VERSION 5.7 ;
BUSBITCHARS "[]" ;
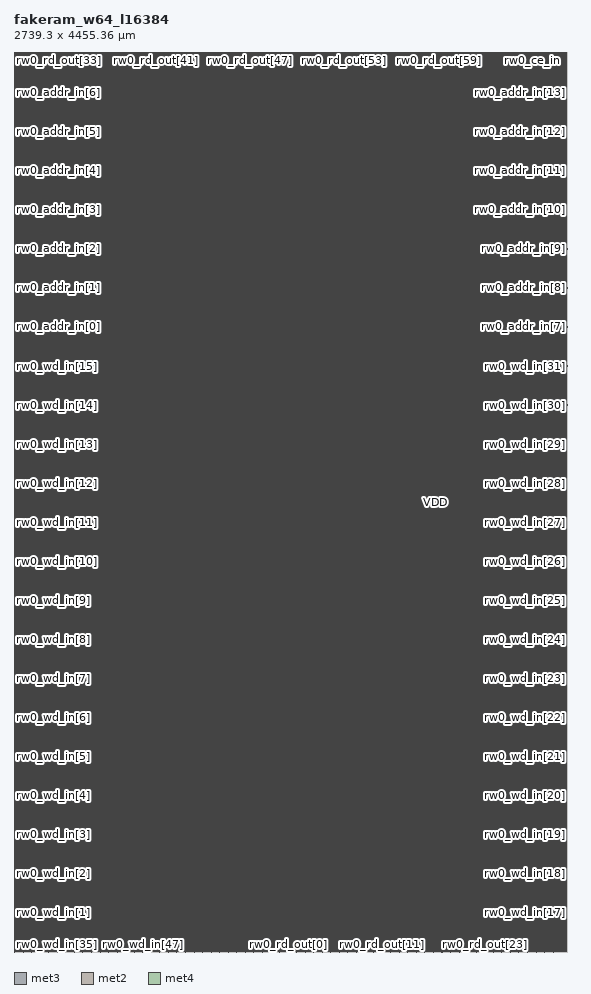
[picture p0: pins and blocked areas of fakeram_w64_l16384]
MACRO fakeram_w64_l16384
  FOREIGN fakeram_w64_l16384 0 0 ;
  SYMMETRY X Y R90 ;
  SIZE 2739.300 BY 4455.360 ;
  CLASS BLOCK ;
  PIN rw0_wd_in[0]
    DIRECTION INPUT ;
    USE SIGNAL ;
    SHAPE ABUTMENT ;
    PORT
      LAYER met3 ;
      RECT 0.000 3.930 0.900 4.230 ;
    END
  END rw0_wd_in[0]
  PIN rw0_wd_in[1]
    DIRECTION INPUT ;
    USE SIGNAL ;
    SHAPE ABUTMENT ;
    PORT
      LAYER met3 ;
      RECT 0.000 197.050 0.900 197.350 ;
    END
  END rw0_wd_in[1]
  PIN rw0_wd_in[2]
    DIRECTION INPUT ;
    USE SIGNAL ;
    SHAPE ABUTMENT ;
    PORT
      LAYER met3 ;
      RECT 0.000 390.170 0.900 390.470 ;
    END
  END rw0_wd_in[2]
  PIN rw0_wd_in[3]
    DIRECTION INPUT ;
    USE SIGNAL ;
    SHAPE ABUTMENT ;
    PORT
      LAYER met3 ;
      RECT 0.000 583.290 0.900 583.590 ;
    END
  END rw0_wd_in[3]
  PIN rw0_wd_in[4]
    DIRECTION INPUT ;
    USE SIGNAL ;
    SHAPE ABUTMENT ;
    PORT
      LAYER met3 ;
      RECT 0.000 776.410 0.900 776.710 ;
    END
  END rw0_wd_in[4]
  PIN rw0_wd_in[5]
    DIRECTION INPUT ;
    USE SIGNAL ;
    SHAPE ABUTMENT ;
    PORT
      LAYER met3 ;
      RECT 0.000 969.530 0.900 969.830 ;
    END
  END rw0_wd_in[5]
  PIN rw0_wd_in[6]
    DIRECTION INPUT ;
    USE SIGNAL ;
    SHAPE ABUTMENT ;
    PORT
      LAYER met3 ;
      RECT 0.000 1162.650 0.900 1162.950 ;
    END
  END rw0_wd_in[6]
  PIN rw0_wd_in[7]
    DIRECTION INPUT ;
    USE SIGNAL ;
    SHAPE ABUTMENT ;
    PORT
      LAYER met3 ;
      RECT 0.000 1355.770 0.900 1356.070 ;
    END
  END rw0_wd_in[7]
  PIN rw0_wd_in[8]
    DIRECTION INPUT ;
    USE SIGNAL ;
    SHAPE ABUTMENT ;
    PORT
      LAYER met3 ;
      RECT 0.000 1548.890 0.900 1549.190 ;
    END
  END rw0_wd_in[8]
  PIN rw0_wd_in[9]
    DIRECTION INPUT ;
    USE SIGNAL ;
    SHAPE ABUTMENT ;
    PORT
      LAYER met3 ;
      RECT 0.000 1742.010 0.900 1742.310 ;
    END
  END rw0_wd_in[9]
  PIN rw0_wd_in[10]
    DIRECTION INPUT ;
    USE SIGNAL ;
    SHAPE ABUTMENT ;
    PORT
      LAYER met3 ;
      RECT 0.000 1935.130 0.900 1935.430 ;
    END
  END rw0_wd_in[10]
  PIN rw0_wd_in[11]
    DIRECTION INPUT ;
    USE SIGNAL ;
    SHAPE ABUTMENT ;
    PORT
      LAYER met3 ;
      RECT 0.000 2128.250 0.900 2128.550 ;
    END
  END rw0_wd_in[11]
  PIN rw0_wd_in[12]
    DIRECTION INPUT ;
    USE SIGNAL ;
    SHAPE ABUTMENT ;
    PORT
      LAYER met3 ;
      RECT 0.000 2321.370 0.900 2321.670 ;
    END
  END rw0_wd_in[12]
  PIN rw0_wd_in[13]
    DIRECTION INPUT ;
    USE SIGNAL ;
    SHAPE ABUTMENT ;
    PORT
      LAYER met3 ;
      RECT 0.000 2514.490 0.900 2514.790 ;
    END
  END rw0_wd_in[13]
  PIN rw0_wd_in[14]
    DIRECTION INPUT ;
    USE SIGNAL ;
    SHAPE ABUTMENT ;
    PORT
      LAYER met3 ;
      RECT 0.000 2707.610 0.900 2707.910 ;
    END
  END rw0_wd_in[14]
  PIN rw0_wd_in[15]
    DIRECTION INPUT ;
    USE SIGNAL ;
    SHAPE ABUTMENT ;
    PORT
      LAYER met3 ;
      RECT 0.000 2900.730 0.900 2901.030 ;
    END
  END rw0_wd_in[15]
  PIN rw0_wd_in[16]
    DIRECTION INPUT ;
    USE SIGNAL ;
    SHAPE ABUTMENT ;
    PORT
      LAYER met3 ;
      RECT 2738.400 3.930 2739.300 4.230 ;
    END
  END rw0_wd_in[16]
  PIN rw0_wd_in[17]
    DIRECTION INPUT ;
    USE SIGNAL ;
    SHAPE ABUTMENT ;
    PORT
      LAYER met3 ;
      RECT 2738.400 197.050 2739.300 197.350 ;
    END
  END rw0_wd_in[17]
  PIN rw0_wd_in[18]
    DIRECTION INPUT ;
    USE SIGNAL ;
    SHAPE ABUTMENT ;
    PORT
      LAYER met3 ;
      RECT 2738.400 390.170 2739.300 390.470 ;
    END
  END rw0_wd_in[18]
  PIN rw0_wd_in[19]
    DIRECTION INPUT ;
    USE SIGNAL ;
    SHAPE ABUTMENT ;
    PORT
      LAYER met3 ;
      RECT 2738.400 583.290 2739.300 583.590 ;
    END
  END rw0_wd_in[19]
  PIN rw0_wd_in[20]
    DIRECTION INPUT ;
    USE SIGNAL ;
    SHAPE ABUTMENT ;
    PORT
      LAYER met3 ;
      RECT 2738.400 776.410 2739.300 776.710 ;
    END
  END rw0_wd_in[20]
  PIN rw0_wd_in[21]
    DIRECTION INPUT ;
    USE SIGNAL ;
    SHAPE ABUTMENT ;
    PORT
      LAYER met3 ;
      RECT 2738.400 969.530 2739.300 969.830 ;
    END
  END rw0_wd_in[21]
  PIN rw0_wd_in[22]
    DIRECTION INPUT ;
    USE SIGNAL ;
    SHAPE ABUTMENT ;
    PORT
      LAYER met3 ;
      RECT 2738.400 1162.650 2739.300 1162.950 ;
    END
  END rw0_wd_in[22]
  PIN rw0_wd_in[23]
    DIRECTION INPUT ;
    USE SIGNAL ;
    SHAPE ABUTMENT ;
    PORT
      LAYER met3 ;
      RECT 2738.400 1355.770 2739.300 1356.070 ;
    END
  END rw0_wd_in[23]
  PIN rw0_wd_in[24]
    DIRECTION INPUT ;
    USE SIGNAL ;
    SHAPE ABUTMENT ;
    PORT
      LAYER met3 ;
      RECT 2738.400 1548.890 2739.300 1549.190 ;
    END
  END rw0_wd_in[24]
  PIN rw0_wd_in[25]
    DIRECTION INPUT ;
    USE SIGNAL ;
    SHAPE ABUTMENT ;
    PORT
      LAYER met3 ;
      RECT 2738.400 1742.010 2739.300 1742.310 ;
    END
  END rw0_wd_in[25]
  PIN rw0_wd_in[26]
    DIRECTION INPUT ;
    USE SIGNAL ;
    SHAPE ABUTMENT ;
    PORT
      LAYER met3 ;
      RECT 2738.400 1935.130 2739.300 1935.430 ;
    END
  END rw0_wd_in[26]
  PIN rw0_wd_in[27]
    DIRECTION INPUT ;
    USE SIGNAL ;
    SHAPE ABUTMENT ;
    PORT
      LAYER met3 ;
      RECT 2738.400 2128.250 2739.300 2128.550 ;
    END
  END rw0_wd_in[27]
  PIN rw0_wd_in[28]
    DIRECTION INPUT ;
    USE SIGNAL ;
    SHAPE ABUTMENT ;
    PORT
      LAYER met3 ;
      RECT 2738.400 2321.370 2739.300 2321.670 ;
    END
  END rw0_wd_in[28]
  PIN rw0_wd_in[29]
    DIRECTION INPUT ;
    USE SIGNAL ;
    SHAPE ABUTMENT ;
    PORT
      LAYER met3 ;
      RECT 2738.400 2514.490 2739.300 2514.790 ;
    END
  END rw0_wd_in[29]
  PIN rw0_wd_in[30]
    DIRECTION INPUT ;
    USE SIGNAL ;
    SHAPE ABUTMENT ;
    PORT
      LAYER met3 ;
      RECT 2738.400 2707.610 2739.300 2707.910 ;
    END
  END rw0_wd_in[30]
  PIN rw0_wd_in[31]
    DIRECTION INPUT ;
    USE SIGNAL ;
    SHAPE ABUTMENT ;
    PORT
      LAYER met3 ;
      RECT 2738.400 2900.730 2739.300 2901.030 ;
    END
  END rw0_wd_in[31]
  PIN rw0_wd_in[32]
    DIRECTION INPUT ;
    USE SIGNAL ;
    SHAPE ABUTMENT ;
    PORT
      LAYER met2 ;
      RECT 2.690 0.000 2.830 0.420 ;
    END
  END rw0_wd_in[32]
  PIN rw0_wd_in[33]
    DIRECTION INPUT ;
    USE SIGNAL ;
    SHAPE ABUTMENT ;
    PORT
      LAYER met2 ;
      RECT 45.010 0.000 45.150 0.420 ;
    END
  END rw0_wd_in[33]
  PIN rw0_wd_in[34]
    DIRECTION INPUT ;
    USE SIGNAL ;
    SHAPE ABUTMENT ;
    PORT
      LAYER met2 ;
      RECT 87.330 0.000 87.470 0.420 ;
    END
  END rw0_wd_in[34]
  PIN rw0_wd_in[35]
    DIRECTION INPUT ;
    USE SIGNAL ;
    SHAPE ABUTMENT ;
    PORT
      LAYER met2 ;
      RECT 129.650 0.000 129.790 0.420 ;
    END
  END rw0_wd_in[35]
  PIN rw0_wd_in[36]
    DIRECTION INPUT ;
    USE SIGNAL ;
    SHAPE ABUTMENT ;
    PORT
      LAYER met2 ;
      RECT 171.970 0.000 172.110 0.420 ;
    END
  END rw0_wd_in[36]
  PIN rw0_wd_in[37]
    DIRECTION INPUT ;
    USE SIGNAL ;
    SHAPE ABUTMENT ;
    PORT
      LAYER met2 ;
      RECT 214.290 0.000 214.430 0.420 ;
    END
  END rw0_wd_in[37]
  PIN rw0_wd_in[38]
    DIRECTION INPUT ;
    USE SIGNAL ;
    SHAPE ABUTMENT ;
    PORT
      LAYER met2 ;
      RECT 256.610 0.000 256.750 0.420 ;
    END
  END rw0_wd_in[38]
  PIN rw0_wd_in[39]
    DIRECTION INPUT ;
    USE SIGNAL ;
    SHAPE ABUTMENT ;
    PORT
      LAYER met2 ;
      RECT 298.930 0.000 299.070 0.420 ;
    END
  END rw0_wd_in[39]
  PIN rw0_wd_in[40]
    DIRECTION INPUT ;
    USE SIGNAL ;
    SHAPE ABUTMENT ;
    PORT
      LAYER met2 ;
      RECT 341.250 0.000 341.390 0.420 ;
    END
  END rw0_wd_in[40]
  PIN rw0_wd_in[41]
    DIRECTION INPUT ;
    USE SIGNAL ;
    SHAPE ABUTMENT ;
    PORT
      LAYER met2 ;
      RECT 383.570 0.000 383.710 0.420 ;
    END
  END rw0_wd_in[41]
  PIN rw0_wd_in[42]
    DIRECTION INPUT ;
    USE SIGNAL ;
    SHAPE ABUTMENT ;
    PORT
      LAYER met2 ;
      RECT 425.890 0.000 426.030 0.420 ;
    END
  END rw0_wd_in[42]
  PIN rw0_wd_in[43]
    DIRECTION INPUT ;
    USE SIGNAL ;
    SHAPE ABUTMENT ;
    PORT
      LAYER met2 ;
      RECT 468.210 0.000 468.350 0.420 ;
    END
  END rw0_wd_in[43]
  PIN rw0_wd_in[44]
    DIRECTION INPUT ;
    USE SIGNAL ;
    SHAPE ABUTMENT ;
    PORT
      LAYER met2 ;
      RECT 510.530 0.000 510.670 0.420 ;
    END
  END rw0_wd_in[44]
  PIN rw0_wd_in[45]
    DIRECTION INPUT ;
    USE SIGNAL ;
    SHAPE ABUTMENT ;
    PORT
      LAYER met2 ;
      RECT 552.850 0.000 552.990 0.420 ;
    END
  END rw0_wd_in[45]
  PIN rw0_wd_in[46]
    DIRECTION INPUT ;
    USE SIGNAL ;
    SHAPE ABUTMENT ;
    PORT
      LAYER met2 ;
      RECT 595.170 0.000 595.310 0.420 ;
    END
  END rw0_wd_in[46]
  PIN rw0_wd_in[47]
    DIRECTION INPUT ;
    USE SIGNAL ;
    SHAPE ABUTMENT ;
    PORT
      LAYER met2 ;
      RECT 637.490 0.000 637.630 0.420 ;
    END
  END rw0_wd_in[47]
  PIN rw0_wd_in[48]
    DIRECTION INPUT ;
    USE SIGNAL ;
    SHAPE ABUTMENT ;
    PORT
      LAYER met2 ;
      RECT 679.810 0.000 679.950 0.420 ;
    END
  END rw0_wd_in[48]
  PIN rw0_wd_in[49]
    DIRECTION INPUT ;
    USE SIGNAL ;
    SHAPE ABUTMENT ;
    PORT
      LAYER met2 ;
      RECT 722.130 0.000 722.270 0.420 ;
    END
  END rw0_wd_in[49]
  PIN rw0_wd_in[50]
    DIRECTION INPUT ;
    USE SIGNAL ;
    SHAPE ABUTMENT ;
    PORT
      LAYER met2 ;
      RECT 764.450 0.000 764.590 0.420 ;
    END
  END rw0_wd_in[50]
  PIN rw0_wd_in[51]
    DIRECTION INPUT ;
    USE SIGNAL ;
    SHAPE ABUTMENT ;
    PORT
      LAYER met2 ;
      RECT 806.770 0.000 806.910 0.420 ;
    END
  END rw0_wd_in[51]
  PIN rw0_wd_in[52]
    DIRECTION INPUT ;
    USE SIGNAL ;
    SHAPE ABUTMENT ;
    PORT
      LAYER met2 ;
      RECT 849.090 0.000 849.230 0.420 ;
    END
  END rw0_wd_in[52]
  PIN rw0_wd_in[53]
    DIRECTION INPUT ;
    USE SIGNAL ;
    SHAPE ABUTMENT ;
    PORT
      LAYER met2 ;
      RECT 891.410 0.000 891.550 0.420 ;
    END
  END rw0_wd_in[53]
  PIN rw0_wd_in[54]
    DIRECTION INPUT ;
    USE SIGNAL ;
    SHAPE ABUTMENT ;
    PORT
      LAYER met2 ;
      RECT 933.730 0.000 933.870 0.420 ;
    END
  END rw0_wd_in[54]
  PIN rw0_wd_in[55]
    DIRECTION INPUT ;
    USE SIGNAL ;
    SHAPE ABUTMENT ;
    PORT
      LAYER met2 ;
      RECT 976.050 0.000 976.190 0.420 ;
    END
  END rw0_wd_in[55]
  PIN rw0_wd_in[56]
    DIRECTION INPUT ;
    USE SIGNAL ;
    SHAPE ABUTMENT ;
    PORT
      LAYER met2 ;
      RECT 1018.370 0.000 1018.510 0.420 ;
    END
  END rw0_wd_in[56]
  PIN rw0_wd_in[57]
    DIRECTION INPUT ;
    USE SIGNAL ;
    SHAPE ABUTMENT ;
    PORT
      LAYER met2 ;
      RECT 1060.690 0.000 1060.830 0.420 ;
    END
  END rw0_wd_in[57]
  PIN rw0_wd_in[58]
    DIRECTION INPUT ;
    USE SIGNAL ;
    SHAPE ABUTMENT ;
    PORT
      LAYER met2 ;
      RECT 1103.010 0.000 1103.150 0.420 ;
    END
  END rw0_wd_in[58]
  PIN rw0_wd_in[59]
    DIRECTION INPUT ;
    USE SIGNAL ;
    SHAPE ABUTMENT ;
    PORT
      LAYER met2 ;
      RECT 1145.330 0.000 1145.470 0.420 ;
    END
  END rw0_wd_in[59]
  PIN rw0_wd_in[60]
    DIRECTION INPUT ;
    USE SIGNAL ;
    SHAPE ABUTMENT ;
    PORT
      LAYER met2 ;
      RECT 1187.650 0.000 1187.790 0.420 ;
    END
  END rw0_wd_in[60]
  PIN rw0_wd_in[61]
    DIRECTION INPUT ;
    USE SIGNAL ;
    SHAPE ABUTMENT ;
    PORT
      LAYER met2 ;
      RECT 1229.970 0.000 1230.110 0.420 ;
    END
  END rw0_wd_in[61]
  PIN rw0_wd_in[62]
    DIRECTION INPUT ;
    USE SIGNAL ;
    SHAPE ABUTMENT ;
    PORT
      LAYER met2 ;
      RECT 1272.290 0.000 1272.430 0.420 ;
    END
  END rw0_wd_in[62]
  PIN rw0_wd_in[63]
    DIRECTION INPUT ;
    USE SIGNAL ;
    SHAPE ABUTMENT ;
    PORT
      LAYER met2 ;
      RECT 1314.610 0.000 1314.750 0.420 ;
    END
  END rw0_wd_in[63]
  PIN rw0_rd_out[0]
    DIRECTION OUTPUT ;
    USE SIGNAL ;
    SHAPE ABUTMENT ;
    PORT
      LAYER met2 ;
      RECT 1356.930 0.000 1357.070 0.420 ;
    END
  END rw0_rd_out[0]
  PIN rw0_rd_out[1]
    DIRECTION OUTPUT ;
    USE SIGNAL ;
    SHAPE ABUTMENT ;
    PORT
      LAYER met2 ;
      RECT 1399.250 0.000 1399.390 0.420 ;
    END
  END rw0_rd_out[1]
  PIN rw0_rd_out[2]
    DIRECTION OUTPUT ;
    USE SIGNAL ;
    SHAPE ABUTMENT ;
    PORT
      LAYER met2 ;
      RECT 1441.570 0.000 1441.710 0.420 ;
    END
  END rw0_rd_out[2]
  PIN rw0_rd_out[3]
    DIRECTION OUTPUT ;
    USE SIGNAL ;
    SHAPE ABUTMENT ;
    PORT
      LAYER met2 ;
      RECT 1483.890 0.000 1484.030 0.420 ;
    END
  END rw0_rd_out[3]
  PIN rw0_rd_out[4]
    DIRECTION OUTPUT ;
    USE SIGNAL ;
    SHAPE ABUTMENT ;
    PORT
      LAYER met2 ;
      RECT 1526.210 0.000 1526.350 0.420 ;
    END
  END rw0_rd_out[4]
  PIN rw0_rd_out[5]
    DIRECTION OUTPUT ;
    USE SIGNAL ;
    SHAPE ABUTMENT ;
    PORT
      LAYER met2 ;
      RECT 1568.530 0.000 1568.670 0.420 ;
    END
  END rw0_rd_out[5]
  PIN rw0_rd_out[6]
    DIRECTION OUTPUT ;
    USE SIGNAL ;
    SHAPE ABUTMENT ;
    PORT
      LAYER met2 ;
      RECT 1610.850 0.000 1610.990 0.420 ;
    END
  END rw0_rd_out[6]
  PIN rw0_rd_out[7]
    DIRECTION OUTPUT ;
    USE SIGNAL ;
    SHAPE ABUTMENT ;
    PORT
      LAYER met2 ;
      RECT 1653.170 0.000 1653.310 0.420 ;
    END
  END rw0_rd_out[7]
  PIN rw0_rd_out[8]
    DIRECTION OUTPUT ;
    USE SIGNAL ;
    SHAPE ABUTMENT ;
    PORT
      LAYER met2 ;
      RECT 1695.490 0.000 1695.630 0.420 ;
    END
  END rw0_rd_out[8]
  PIN rw0_rd_out[9]
    DIRECTION OUTPUT ;
    USE SIGNAL ;
    SHAPE ABUTMENT ;
    PORT
      LAYER met2 ;
      RECT 1737.810 0.000 1737.950 0.420 ;
    END
  END rw0_rd_out[9]
  PIN rw0_rd_out[10]
    DIRECTION OUTPUT ;
    USE SIGNAL ;
    SHAPE ABUTMENT ;
    PORT
      LAYER met2 ;
      RECT 1780.130 0.000 1780.270 0.420 ;
    END
  END rw0_rd_out[10]
  PIN rw0_rd_out[11]
    DIRECTION OUTPUT ;
    USE SIGNAL ;
    SHAPE ABUTMENT ;
    PORT
      LAYER met2 ;
      RECT 1822.450 0.000 1822.590 0.420 ;
    END
  END rw0_rd_out[11]
  PIN rw0_rd_out[12]
    DIRECTION OUTPUT ;
    USE SIGNAL ;
    SHAPE ABUTMENT ;
    PORT
      LAYER met2 ;
      RECT 1864.770 0.000 1864.910 0.420 ;
    END
  END rw0_rd_out[12]
  PIN rw0_rd_out[13]
    DIRECTION OUTPUT ;
    USE SIGNAL ;
    SHAPE ABUTMENT ;
    PORT
      LAYER met2 ;
      RECT 1907.090 0.000 1907.230 0.420 ;
    END
  END rw0_rd_out[13]
  PIN rw0_rd_out[14]
    DIRECTION OUTPUT ;
    USE SIGNAL ;
    SHAPE ABUTMENT ;
    PORT
      LAYER met2 ;
      RECT 1949.410 0.000 1949.550 0.420 ;
    END
  END rw0_rd_out[14]
  PIN rw0_rd_out[15]
    DIRECTION OUTPUT ;
    USE SIGNAL ;
    SHAPE ABUTMENT ;
    PORT
      LAYER met2 ;
      RECT 1991.730 0.000 1991.870 0.420 ;
    END
  END rw0_rd_out[15]
  PIN rw0_rd_out[16]
    DIRECTION OUTPUT ;
    USE SIGNAL ;
    SHAPE ABUTMENT ;
    PORT
      LAYER met2 ;
      RECT 2034.050 0.000 2034.190 0.420 ;
    END
  END rw0_rd_out[16]
  PIN rw0_rd_out[17]
    DIRECTION OUTPUT ;
    USE SIGNAL ;
    SHAPE ABUTMENT ;
    PORT
      LAYER met2 ;
      RECT 2076.370 0.000 2076.510 0.420 ;
    END
  END rw0_rd_out[17]
  PIN rw0_rd_out[18]
    DIRECTION OUTPUT ;
    USE SIGNAL ;
    SHAPE ABUTMENT ;
    PORT
      LAYER met2 ;
      RECT 2118.690 0.000 2118.830 0.420 ;
    END
  END rw0_rd_out[18]
  PIN rw0_rd_out[19]
    DIRECTION OUTPUT ;
    USE SIGNAL ;
    SHAPE ABUTMENT ;
    PORT
      LAYER met2 ;
      RECT 2161.010 0.000 2161.150 0.420 ;
    END
  END rw0_rd_out[19]
  PIN rw0_rd_out[20]
    DIRECTION OUTPUT ;
    USE SIGNAL ;
    SHAPE ABUTMENT ;
    PORT
      LAYER met2 ;
      RECT 2203.330 0.000 2203.470 0.420 ;
    END
  END rw0_rd_out[20]
  PIN rw0_rd_out[21]
    DIRECTION OUTPUT ;
    USE SIGNAL ;
    SHAPE ABUTMENT ;
    PORT
      LAYER met2 ;
      RECT 2245.650 0.000 2245.790 0.420 ;
    END
  END rw0_rd_out[21]
  PIN rw0_rd_out[22]
    DIRECTION OUTPUT ;
    USE SIGNAL ;
    SHAPE ABUTMENT ;
    PORT
      LAYER met2 ;
      RECT 2287.970 0.000 2288.110 0.420 ;
    END
  END rw0_rd_out[22]
  PIN rw0_rd_out[23]
    DIRECTION OUTPUT ;
    USE SIGNAL ;
    SHAPE ABUTMENT ;
    PORT
      LAYER met2 ;
      RECT 2330.290 0.000 2330.430 0.420 ;
    END
  END rw0_rd_out[23]
  PIN rw0_rd_out[24]
    DIRECTION OUTPUT ;
    USE SIGNAL ;
    SHAPE ABUTMENT ;
    PORT
      LAYER met2 ;
      RECT 2372.610 0.000 2372.750 0.420 ;
    END
  END rw0_rd_out[24]
  PIN rw0_rd_out[25]
    DIRECTION OUTPUT ;
    USE SIGNAL ;
    SHAPE ABUTMENT ;
    PORT
      LAYER met2 ;
      RECT 2414.930 0.000 2415.070 0.420 ;
    END
  END rw0_rd_out[25]
  PIN rw0_rd_out[26]
    DIRECTION OUTPUT ;
    USE SIGNAL ;
    SHAPE ABUTMENT ;
    PORT
      LAYER met2 ;
      RECT 2457.250 0.000 2457.390 0.420 ;
    END
  END rw0_rd_out[26]
  PIN rw0_rd_out[27]
    DIRECTION OUTPUT ;
    USE SIGNAL ;
    SHAPE ABUTMENT ;
    PORT
      LAYER met2 ;
      RECT 2499.570 0.000 2499.710 0.420 ;
    END
  END rw0_rd_out[27]
  PIN rw0_rd_out[28]
    DIRECTION OUTPUT ;
    USE SIGNAL ;
    SHAPE ABUTMENT ;
    PORT
      LAYER met2 ;
      RECT 2541.890 0.000 2542.030 0.420 ;
    END
  END rw0_rd_out[28]
  PIN rw0_rd_out[29]
    DIRECTION OUTPUT ;
    USE SIGNAL ;
    SHAPE ABUTMENT ;
    PORT
      LAYER met2 ;
      RECT 2584.210 0.000 2584.350 0.420 ;
    END
  END rw0_rd_out[29]
  PIN rw0_rd_out[30]
    DIRECTION OUTPUT ;
    USE SIGNAL ;
    SHAPE ABUTMENT ;
    PORT
      LAYER met2 ;
      RECT 2626.530 0.000 2626.670 0.420 ;
    END
  END rw0_rd_out[30]
  PIN rw0_rd_out[31]
    DIRECTION OUTPUT ;
    USE SIGNAL ;
    SHAPE ABUTMENT ;
    PORT
      LAYER met2 ;
      RECT 2668.850 0.000 2668.990 0.420 ;
    END
  END rw0_rd_out[31]
  PIN rw0_rd_out[32]
    DIRECTION OUTPUT ;
    USE SIGNAL ;
    SHAPE ABUTMENT ;
    PORT
      LAYER met2 ;
      RECT 2.690 4454.940 2.830 4455.360 ;
    END
  END rw0_rd_out[32]
  PIN rw0_rd_out[33]
    DIRECTION OUTPUT ;
    USE SIGNAL ;
    SHAPE ABUTMENT ;
    PORT
      LAYER met2 ;
      RECT 80.430 4454.940 80.570 4455.360 ;
    END
  END rw0_rd_out[33]
  PIN rw0_rd_out[34]
    DIRECTION OUTPUT ;
    USE SIGNAL ;
    SHAPE ABUTMENT ;
    PORT
      LAYER met2 ;
      RECT 158.170 4454.940 158.310 4455.360 ;
    END
  END rw0_rd_out[34]
  PIN rw0_rd_out[35]
    DIRECTION OUTPUT ;
    USE SIGNAL ;
    SHAPE ABUTMENT ;
    PORT
      LAYER met2 ;
      RECT 235.910 4454.940 236.050 4455.360 ;
    END
  END rw0_rd_out[35]
  PIN rw0_rd_out[36]
    DIRECTION OUTPUT ;
    USE SIGNAL ;
    SHAPE ABUTMENT ;
    PORT
      LAYER met2 ;
      RECT 313.650 4454.940 313.790 4455.360 ;
    END
  END rw0_rd_out[36]
  PIN rw0_rd_out[37]
    DIRECTION OUTPUT ;
    USE SIGNAL ;
    SHAPE ABUTMENT ;
    PORT
      LAYER met2 ;
      RECT 391.390 4454.940 391.530 4455.360 ;
    END
  END rw0_rd_out[37]
  PIN rw0_rd_out[38]
    DIRECTION OUTPUT ;
    USE SIGNAL ;
    SHAPE ABUTMENT ;
    PORT
      LAYER met2 ;
      RECT 469.130 4454.940 469.270 4455.360 ;
    END
  END rw0_rd_out[38]
  PIN rw0_rd_out[39]
    DIRECTION OUTPUT ;
    USE SIGNAL ;
    SHAPE ABUTMENT ;
    PORT
      LAYER met2 ;
      RECT 546.870 4454.940 547.010 4455.360 ;
    END
  END rw0_rd_out[39]
  PIN rw0_rd_out[40]
    DIRECTION OUTPUT ;
    USE SIGNAL ;
    SHAPE ABUTMENT ;
    PORT
      LAYER met2 ;
      RECT 624.610 4454.940 624.750 4455.360 ;
    END
  END rw0_rd_out[40]
  PIN rw0_rd_out[41]
    DIRECTION OUTPUT ;
    USE SIGNAL ;
    SHAPE ABUTMENT ;
    PORT
      LAYER met2 ;
      RECT 702.350 4454.940 702.490 4455.360 ;
    END
  END rw0_rd_out[41]
  PIN rw0_rd_out[42]
    DIRECTION OUTPUT ;
    USE SIGNAL ;
    SHAPE ABUTMENT ;
    PORT
      LAYER met2 ;
      RECT 780.090 4454.940 780.230 4455.360 ;
    END
  END rw0_rd_out[42]
  PIN rw0_rd_out[43]
    DIRECTION OUTPUT ;
    USE SIGNAL ;
    SHAPE ABUTMENT ;
    PORT
      LAYER met2 ;
      RECT 857.830 4454.940 857.970 4455.360 ;
    END
  END rw0_rd_out[43]
  PIN rw0_rd_out[44]
    DIRECTION OUTPUT ;
    USE SIGNAL ;
    SHAPE ABUTMENT ;
    PORT
      LAYER met2 ;
      RECT 935.570 4454.940 935.710 4455.360 ;
    END
  END rw0_rd_out[44]
  PIN rw0_rd_out[45]
    DIRECTION OUTPUT ;
    USE SIGNAL ;
    SHAPE ABUTMENT ;
    PORT
      LAYER met2 ;
      RECT 1013.310 4454.940 1013.450 4455.360 ;
    END
  END rw0_rd_out[45]
  PIN rw0_rd_out[46]
    DIRECTION OUTPUT ;
    USE SIGNAL ;
    SHAPE ABUTMENT ;
    PORT
      LAYER met2 ;
      RECT 1091.050 4454.940 1091.190 4455.360 ;
    END
  END rw0_rd_out[46]
  PIN rw0_rd_out[47]
    DIRECTION OUTPUT ;
    USE SIGNAL ;
    SHAPE ABUTMENT ;
    PORT
      LAYER met2 ;
      RECT 1168.790 4454.940 1168.930 4455.360 ;
    END
  END rw0_rd_out[47]
  PIN rw0_rd_out[48]
    DIRECTION OUTPUT ;
    USE SIGNAL ;
    SHAPE ABUTMENT ;
    PORT
      LAYER met2 ;
      RECT 1246.530 4454.940 1246.670 4455.360 ;
    END
  END rw0_rd_out[48]
  PIN rw0_rd_out[49]
    DIRECTION OUTPUT ;
    USE SIGNAL ;
    SHAPE ABUTMENT ;
    PORT
      LAYER met2 ;
      RECT 1324.270 4454.940 1324.410 4455.360 ;
    END
  END rw0_rd_out[49]
  PIN rw0_rd_out[50]
    DIRECTION OUTPUT ;
    USE SIGNAL ;
    SHAPE ABUTMENT ;
    PORT
      LAYER met2 ;
      RECT 1402.010 4454.940 1402.150 4455.360 ;
    END
  END rw0_rd_out[50]
  PIN rw0_rd_out[51]
    DIRECTION OUTPUT ;
    USE SIGNAL ;
    SHAPE ABUTMENT ;
    PORT
      LAYER met2 ;
      RECT 1479.750 4454.940 1479.890 4455.360 ;
    END
  END rw0_rd_out[51]
  PIN rw0_rd_out[52]
    DIRECTION OUTPUT ;
    USE SIGNAL ;
    SHAPE ABUTMENT ;
    PORT
      LAYER met2 ;
      RECT 1557.490 4454.940 1557.630 4455.360 ;
    END
  END rw0_rd_out[52]
  PIN rw0_rd_out[53]
    DIRECTION OUTPUT ;
    USE SIGNAL ;
    SHAPE ABUTMENT ;
    PORT
      LAYER met2 ;
      RECT 1635.230 4454.940 1635.370 4455.360 ;
    END
  END rw0_rd_out[53]
  PIN rw0_rd_out[54]
    DIRECTION OUTPUT ;
    USE SIGNAL ;
    SHAPE ABUTMENT ;
    PORT
      LAYER met2 ;
      RECT 1712.970 4454.940 1713.110 4455.360 ;
    END
  END rw0_rd_out[54]
  PIN rw0_rd_out[55]
    DIRECTION OUTPUT ;
    USE SIGNAL ;
    SHAPE ABUTMENT ;
    PORT
      LAYER met2 ;
      RECT 1790.710 4454.940 1790.850 4455.360 ;
    END
  END rw0_rd_out[55]
  PIN rw0_rd_out[56]
    DIRECTION OUTPUT ;
    USE SIGNAL ;
    SHAPE ABUTMENT ;
    PORT
      LAYER met2 ;
      RECT 1868.450 4454.940 1868.590 4455.360 ;
    END
  END rw0_rd_out[56]
  PIN rw0_rd_out[57]
    DIRECTION OUTPUT ;
    USE SIGNAL ;
    SHAPE ABUTMENT ;
    PORT
      LAYER met2 ;
      RECT 1946.190 4454.940 1946.330 4455.360 ;
    END
  END rw0_rd_out[57]
  PIN rw0_rd_out[58]
    DIRECTION OUTPUT ;
    USE SIGNAL ;
    SHAPE ABUTMENT ;
    PORT
      LAYER met2 ;
      RECT 2023.930 4454.940 2024.070 4455.360 ;
    END
  END rw0_rd_out[58]
  PIN rw0_rd_out[59]
    DIRECTION OUTPUT ;
    USE SIGNAL ;
    SHAPE ABUTMENT ;
    PORT
      LAYER met2 ;
      RECT 2101.670 4454.940 2101.810 4455.360 ;
    END
  END rw0_rd_out[59]
  PIN rw0_rd_out[60]
    DIRECTION OUTPUT ;
    USE SIGNAL ;
    SHAPE ABUTMENT ;
    PORT
      LAYER met2 ;
      RECT 2179.410 4454.940 2179.550 4455.360 ;
    END
  END rw0_rd_out[60]
  PIN rw0_rd_out[61]
    DIRECTION OUTPUT ;
    USE SIGNAL ;
    SHAPE ABUTMENT ;
    PORT
      LAYER met2 ;
      RECT 2257.150 4454.940 2257.290 4455.360 ;
    END
  END rw0_rd_out[61]
  PIN rw0_rd_out[62]
    DIRECTION OUTPUT ;
    USE SIGNAL ;
    SHAPE ABUTMENT ;
    PORT
      LAYER met2 ;
      RECT 2334.890 4454.940 2335.030 4455.360 ;
    END
  END rw0_rd_out[62]
  PIN rw0_rd_out[63]
    DIRECTION OUTPUT ;
    USE SIGNAL ;
    SHAPE ABUTMENT ;
    PORT
      LAYER met2 ;
      RECT 2412.630 4454.940 2412.770 4455.360 ;
    END
  END rw0_rd_out[63]
  PIN rw0_addr_in[0]
    DIRECTION INPUT ;
    USE SIGNAL ;
    SHAPE ABUTMENT ;
    PORT
      LAYER met3 ;
      RECT 0.000 3093.850 0.900 3094.150 ;
    END
  END rw0_addr_in[0]
  PIN rw0_addr_in[1]
    DIRECTION INPUT ;
    USE SIGNAL ;
    SHAPE ABUTMENT ;
    PORT
      LAYER met3 ;
      RECT 0.000 3286.970 0.900 3287.270 ;
    END
  END rw0_addr_in[1]
  PIN rw0_addr_in[2]
    DIRECTION INPUT ;
    USE SIGNAL ;
    SHAPE ABUTMENT ;
    PORT
      LAYER met3 ;
      RECT 0.000 3480.090 0.900 3480.390 ;
    END
  END rw0_addr_in[2]
  PIN rw0_addr_in[3]
    DIRECTION INPUT ;
    USE SIGNAL ;
    SHAPE ABUTMENT ;
    PORT
      LAYER met3 ;
      RECT 0.000 3673.210 0.900 3673.510 ;
    END
  END rw0_addr_in[3]
  PIN rw0_addr_in[4]
    DIRECTION INPUT ;
    USE SIGNAL ;
    SHAPE ABUTMENT ;
    PORT
      LAYER met3 ;
      RECT 0.000 3866.330 0.900 3866.630 ;
    END
  END rw0_addr_in[4]
  PIN rw0_addr_in[5]
    DIRECTION INPUT ;
    USE SIGNAL ;
    SHAPE ABUTMENT ;
    PORT
      LAYER met3 ;
      RECT 0.000 4059.450 0.900 4059.750 ;
    END
  END rw0_addr_in[5]
  PIN rw0_addr_in[6]
    DIRECTION INPUT ;
    USE SIGNAL ;
    SHAPE ABUTMENT ;
    PORT
      LAYER met3 ;
      RECT 0.000 4252.570 0.900 4252.870 ;
    END
  END rw0_addr_in[6]
  PIN rw0_addr_in[7]
    DIRECTION INPUT ;
    USE SIGNAL ;
    SHAPE ABUTMENT ;
    PORT
      LAYER met3 ;
      RECT 2738.400 3093.850 2739.300 3094.150 ;
    END
  END rw0_addr_in[7]
  PIN rw0_addr_in[8]
    DIRECTION INPUT ;
    USE SIGNAL ;
    SHAPE ABUTMENT ;
    PORT
      LAYER met3 ;
      RECT 2738.400 3286.970 2739.300 3287.270 ;
    END
  END rw0_addr_in[8]
  PIN rw0_addr_in[9]
    DIRECTION INPUT ;
    USE SIGNAL ;
    SHAPE ABUTMENT ;
    PORT
      LAYER met3 ;
      RECT 2738.400 3480.090 2739.300 3480.390 ;
    END
  END rw0_addr_in[9]
  PIN rw0_addr_in[10]
    DIRECTION INPUT ;
    USE SIGNAL ;
    SHAPE ABUTMENT ;
    PORT
      LAYER met3 ;
      RECT 2738.400 3673.210 2739.300 3673.510 ;
    END
  END rw0_addr_in[10]
  PIN rw0_addr_in[11]
    DIRECTION INPUT ;
    USE SIGNAL ;
    SHAPE ABUTMENT ;
    PORT
      LAYER met3 ;
      RECT 2738.400 3866.330 2739.300 3866.630 ;
    END
  END rw0_addr_in[11]
  PIN rw0_addr_in[12]
    DIRECTION INPUT ;
    USE SIGNAL ;
    SHAPE ABUTMENT ;
    PORT
      LAYER met3 ;
      RECT 2738.400 4059.450 2739.300 4059.750 ;
    END
  END rw0_addr_in[12]
  PIN rw0_addr_in[13]
    DIRECTION INPUT ;
    USE SIGNAL ;
    SHAPE ABUTMENT ;
    PORT
      LAYER met3 ;
      RECT 2738.400 4252.570 2739.300 4252.870 ;
    END
  END rw0_addr_in[13]
  PIN rw0_we_in
    DIRECTION INPUT ;
    USE SIGNAL ;
    SHAPE ABUTMENT ;
    PORT
      LAYER met2 ;
      RECT 2490.370 4454.940 2490.510 4455.360 ;
    END
  END rw0_we_in
  PIN rw0_ce_in
    DIRECTION INPUT ;
    USE SIGNAL ;
    SHAPE ABUTMENT ;
    PORT
      LAYER met2 ;
      RECT 2568.110 4454.940 2568.250 4455.360 ;
    END
  END rw0_ce_in
  PIN rw0_clk
    DIRECTION INPUT ;
    USE SIGNAL ;
    SHAPE ABUTMENT ;
    PORT
      LAYER met2 ;
      RECT 2645.850 4454.940 2645.990 4455.360 ;
    END
  END rw0_clk
  PIN VSS
    DIRECTION INOUT ;
    USE GROUND ;
    PORT
      LAYER met4 ;
      RECT 2.160 4.080 3.360 4451.280 ;
      RECT 13.040 4.080 14.240 4451.280 ;
      RECT 23.920 4.080 25.120 4451.280 ;
      RECT 34.800 4.080 36.000 4451.280 ;
      RECT 45.680 4.080 46.880 4451.280 ;
      RECT 56.560 4.080 57.760 4451.280 ;
      RECT 67.440 4.080 68.640 4451.280 ;
      RECT 78.320 4.080 79.520 4451.280 ;
      RECT 89.200 4.080 90.400 4451.280 ;
      RECT 100.080 4.080 101.280 4451.280 ;
      RECT 110.960 4.080 112.160 4451.280 ;
      RECT 121.840 4.080 123.040 4451.280 ;
      RECT 132.720 4.080 133.920 4451.280 ;
      RECT 143.600 4.080 144.800 4451.280 ;
      RECT 154.480 4.080 155.680 4451.280 ;
      RECT 165.360 4.080 166.560 4451.280 ;
      RECT 176.240 4.080 177.440 4451.280 ;
      RECT 187.120 4.080 188.320 4451.280 ;
      RECT 198.000 4.080 199.200 4451.280 ;
      RECT 208.880 4.080 210.080 4451.280 ;
      RECT 219.760 4.080 220.960 4451.280 ;
      RECT 230.640 4.080 231.840 4451.280 ;
      RECT 241.520 4.080 242.720 4451.280 ;
      RECT 252.400 4.080 253.600 4451.280 ;
      RECT 263.280 4.080 264.480 4451.280 ;
      RECT 274.160 4.080 275.360 4451.280 ;
      RECT 285.040 4.080 286.240 4451.280 ;
      RECT 295.920 4.080 297.120 4451.280 ;
      RECT 306.800 4.080 308.000 4451.280 ;
      RECT 317.680 4.080 318.880 4451.280 ;
      RECT 328.560 4.080 329.760 4451.280 ;
      RECT 339.440 4.080 340.640 4451.280 ;
      RECT 350.320 4.080 351.520 4451.280 ;
      RECT 361.200 4.080 362.400 4451.280 ;
      RECT 372.080 4.080 373.280 4451.280 ;
      RECT 382.960 4.080 384.160 4451.280 ;
      RECT 393.840 4.080 395.040 4451.280 ;
      RECT 404.720 4.080 405.920 4451.280 ;
      RECT 415.600 4.080 416.800 4451.280 ;
      RECT 426.480 4.080 427.680 4451.280 ;
      RECT 437.360 4.080 438.560 4451.280 ;
      RECT 448.240 4.080 449.440 4451.280 ;
      RECT 459.120 4.080 460.320 4451.280 ;
      RECT 470.000 4.080 471.200 4451.280 ;
      RECT 480.880 4.080 482.080 4451.280 ;
      RECT 491.760 4.080 492.960 4451.280 ;
      RECT 502.640 4.080 503.840 4451.280 ;
      RECT 513.520 4.080 514.720 4451.280 ;
      RECT 524.400 4.080 525.600 4451.280 ;
      RECT 535.280 4.080 536.480 4451.280 ;
      RECT 546.160 4.080 547.360 4451.280 ;
      RECT 557.040 4.080 558.240 4451.280 ;
      RECT 567.920 4.080 569.120 4451.280 ;
      RECT 578.800 4.080 580.000 4451.280 ;
      RECT 589.680 4.080 590.880 4451.280 ;
      RECT 600.560 4.080 601.760 4451.280 ;
      RECT 611.440 4.080 612.640 4451.280 ;
      RECT 622.320 4.080 623.520 4451.280 ;
      RECT 633.200 4.080 634.400 4451.280 ;
      RECT 644.080 4.080 645.280 4451.280 ;
      RECT 654.960 4.080 656.160 4451.280 ;
      RECT 665.840 4.080 667.040 4451.280 ;
      RECT 676.720 4.080 677.920 4451.280 ;
      RECT 687.600 4.080 688.800 4451.280 ;
      RECT 698.480 4.080 699.680 4451.280 ;
      RECT 709.360 4.080 710.560 4451.280 ;
      RECT 720.240 4.080 721.440 4451.280 ;
      RECT 731.120 4.080 732.320 4451.280 ;
      RECT 742.000 4.080 743.200 4451.280 ;
      RECT 752.880 4.080 754.080 4451.280 ;
      RECT 763.760 4.080 764.960 4451.280 ;
      RECT 774.640 4.080 775.840 4451.280 ;
      RECT 785.520 4.080 786.720 4451.280 ;
      RECT 796.400 4.080 797.600 4451.280 ;
      RECT 807.280 4.080 808.480 4451.280 ;
      RECT 818.160 4.080 819.360 4451.280 ;
      RECT 829.040 4.080 830.240 4451.280 ;
      RECT 839.920 4.080 841.120 4451.280 ;
      RECT 850.800 4.080 852.000 4451.280 ;
      RECT 861.680 4.080 862.880 4451.280 ;
      RECT 872.560 4.080 873.760 4451.280 ;
      RECT 883.440 4.080 884.640 4451.280 ;
      RECT 894.320 4.080 895.520 4451.280 ;
      RECT 905.200 4.080 906.400 4451.280 ;
      RECT 916.080 4.080 917.280 4451.280 ;
      RECT 926.960 4.080 928.160 4451.280 ;
      RECT 937.840 4.080 939.040 4451.280 ;
      RECT 948.720 4.080 949.920 4451.280 ;
      RECT 959.600 4.080 960.800 4451.280 ;
      RECT 970.480 4.080 971.680 4451.280 ;
      RECT 981.360 4.080 982.560 4451.280 ;
      RECT 992.240 4.080 993.440 4451.280 ;
      RECT 1003.120 4.080 1004.320 4451.280 ;
      RECT 1014.000 4.080 1015.200 4451.280 ;
      RECT 1024.880 4.080 1026.080 4451.280 ;
      RECT 1035.760 4.080 1036.960 4451.280 ;
      RECT 1046.640 4.080 1047.840 4451.280 ;
      RECT 1057.520 4.080 1058.720 4451.280 ;
      RECT 1068.400 4.080 1069.600 4451.280 ;
      RECT 1079.280 4.080 1080.480 4451.280 ;
      RECT 1090.160 4.080 1091.360 4451.280 ;
      RECT 1101.040 4.080 1102.240 4451.280 ;
      RECT 1111.920 4.080 1113.120 4451.280 ;
      RECT 1122.800 4.080 1124.000 4451.280 ;
      RECT 1133.680 4.080 1134.880 4451.280 ;
      RECT 1144.560 4.080 1145.760 4451.280 ;
      RECT 1155.440 4.080 1156.640 4451.280 ;
      RECT 1166.320 4.080 1167.520 4451.280 ;
      RECT 1177.200 4.080 1178.400 4451.280 ;
      RECT 1188.080 4.080 1189.280 4451.280 ;
      RECT 1198.960 4.080 1200.160 4451.280 ;
      RECT 1209.840 4.080 1211.040 4451.280 ;
      RECT 1220.720 4.080 1221.920 4451.280 ;
      RECT 1231.600 4.080 1232.800 4451.280 ;
      RECT 1242.480 4.080 1243.680 4451.280 ;
      RECT 1253.360 4.080 1254.560 4451.280 ;
      RECT 1264.240 4.080 1265.440 4451.280 ;
      RECT 1275.120 4.080 1276.320 4451.280 ;
      RECT 1286.000 4.080 1287.200 4451.280 ;
      RECT 1296.880 4.080 1298.080 4451.280 ;
      RECT 1307.760 4.080 1308.960 4451.280 ;
      RECT 1318.640 4.080 1319.840 4451.280 ;
      RECT 1329.520 4.080 1330.720 4451.280 ;
      RECT 1340.400 4.080 1341.600 4451.280 ;
      RECT 1351.280 4.080 1352.480 4451.280 ;
      RECT 1362.160 4.080 1363.360 4451.280 ;
      RECT 1373.040 4.080 1374.240 4451.280 ;
      RECT 1383.920 4.080 1385.120 4451.280 ;
      RECT 1394.800 4.080 1396.000 4451.280 ;
      RECT 1405.680 4.080 1406.880 4451.280 ;
      RECT 1416.560 4.080 1417.760 4451.280 ;
      RECT 1427.440 4.080 1428.640 4451.280 ;
      RECT 1438.320 4.080 1439.520 4451.280 ;
      RECT 1449.200 4.080 1450.400 4451.280 ;
      RECT 1460.080 4.080 1461.280 4451.280 ;
      RECT 1470.960 4.080 1472.160 4451.280 ;
      RECT 1481.840 4.080 1483.040 4451.280 ;
      RECT 1492.720 4.080 1493.920 4451.280 ;
      RECT 1503.600 4.080 1504.800 4451.280 ;
      RECT 1514.480 4.080 1515.680 4451.280 ;
      RECT 1525.360 4.080 1526.560 4451.280 ;
      RECT 1536.240 4.080 1537.440 4451.280 ;
      RECT 1547.120 4.080 1548.320 4451.280 ;
      RECT 1558.000 4.080 1559.200 4451.280 ;
      RECT 1568.880 4.080 1570.080 4451.280 ;
      RECT 1579.760 4.080 1580.960 4451.280 ;
      RECT 1590.640 4.080 1591.840 4451.280 ;
      RECT 1601.520 4.080 1602.720 4451.280 ;
      RECT 1612.400 4.080 1613.600 4451.280 ;
      RECT 1623.280 4.080 1624.480 4451.280 ;
      RECT 1634.160 4.080 1635.360 4451.280 ;
      RECT 1645.040 4.080 1646.240 4451.280 ;
      RECT 1655.920 4.080 1657.120 4451.280 ;
      RECT 1666.800 4.080 1668.000 4451.280 ;
      RECT 1677.680 4.080 1678.880 4451.280 ;
      RECT 1688.560 4.080 1689.760 4451.280 ;
      RECT 1699.440 4.080 1700.640 4451.280 ;
      RECT 1710.320 4.080 1711.520 4451.280 ;
      RECT 1721.200 4.080 1722.400 4451.280 ;
      RECT 1732.080 4.080 1733.280 4451.280 ;
      RECT 1742.960 4.080 1744.160 4451.280 ;
      RECT 1753.840 4.080 1755.040 4451.280 ;
      RECT 1764.720 4.080 1765.920 4451.280 ;
      RECT 1775.600 4.080 1776.800 4451.280 ;
      RECT 1786.480 4.080 1787.680 4451.280 ;
      RECT 1797.360 4.080 1798.560 4451.280 ;
      RECT 1808.240 4.080 1809.440 4451.280 ;
      RECT 1819.120 4.080 1820.320 4451.280 ;
      RECT 1830.000 4.080 1831.200 4451.280 ;
      RECT 1840.880 4.080 1842.080 4451.280 ;
      RECT 1851.760 4.080 1852.960 4451.280 ;
      RECT 1862.640 4.080 1863.840 4451.280 ;
      RECT 1873.520 4.080 1874.720 4451.280 ;
      RECT 1884.400 4.080 1885.600 4451.280 ;
      RECT 1895.280 4.080 1896.480 4451.280 ;
      RECT 1906.160 4.080 1907.360 4451.280 ;
      RECT 1917.040 4.080 1918.240 4451.280 ;
      RECT 1927.920 4.080 1929.120 4451.280 ;
      RECT 1938.800 4.080 1940.000 4451.280 ;
      RECT 1949.680 4.080 1950.880 4451.280 ;
      RECT 1960.560 4.080 1961.760 4451.280 ;
      RECT 1971.440 4.080 1972.640 4451.280 ;
      RECT 1982.320 4.080 1983.520 4451.280 ;
      RECT 1993.200 4.080 1994.400 4451.280 ;
      RECT 2004.080 4.080 2005.280 4451.280 ;
      RECT 2014.960 4.080 2016.160 4451.280 ;
      RECT 2025.840 4.080 2027.040 4451.280 ;
      RECT 2036.720 4.080 2037.920 4451.280 ;
      RECT 2047.600 4.080 2048.800 4451.280 ;
      RECT 2058.480 4.080 2059.680 4451.280 ;
      RECT 2069.360 4.080 2070.560 4451.280 ;
      RECT 2080.240 4.080 2081.440 4451.280 ;
      RECT 2091.120 4.080 2092.320 4451.280 ;
      RECT 2102.000 4.080 2103.200 4451.280 ;
      RECT 2112.880 4.080 2114.080 4451.280 ;
      RECT 2123.760 4.080 2124.960 4451.280 ;
      RECT 2134.640 4.080 2135.840 4451.280 ;
      RECT 2145.520 4.080 2146.720 4451.280 ;
      RECT 2156.400 4.080 2157.600 4451.280 ;
      RECT 2167.280 4.080 2168.480 4451.280 ;
      RECT 2178.160 4.080 2179.360 4451.280 ;
      RECT 2189.040 4.080 2190.240 4451.280 ;
      RECT 2199.920 4.080 2201.120 4451.280 ;
      RECT 2210.800 4.080 2212.000 4451.280 ;
      RECT 2221.680 4.080 2222.880 4451.280 ;
      RECT 2232.560 4.080 2233.760 4451.280 ;
      RECT 2243.440 4.080 2244.640 4451.280 ;
      RECT 2254.320 4.080 2255.520 4451.280 ;
      RECT 2265.200 4.080 2266.400 4451.280 ;
      RECT 2276.080 4.080 2277.280 4451.280 ;
      RECT 2286.960 4.080 2288.160 4451.280 ;
      RECT 2297.840 4.080 2299.040 4451.280 ;
      RECT 2308.720 4.080 2309.920 4451.280 ;
      RECT 2319.600 4.080 2320.800 4451.280 ;
      RECT 2330.480 4.080 2331.680 4451.280 ;
      RECT 2341.360 4.080 2342.560 4451.280 ;
      RECT 2352.240 4.080 2353.440 4451.280 ;
      RECT 2363.120 4.080 2364.320 4451.280 ;
      RECT 2374.000 4.080 2375.200 4451.280 ;
      RECT 2384.880 4.080 2386.080 4451.280 ;
      RECT 2395.760 4.080 2396.960 4451.280 ;
      RECT 2406.640 4.080 2407.840 4451.280 ;
      RECT 2417.520 4.080 2418.720 4451.280 ;
      RECT 2428.400 4.080 2429.600 4451.280 ;
      RECT 2439.280 4.080 2440.480 4451.280 ;
      RECT 2450.160 4.080 2451.360 4451.280 ;
      RECT 2461.040 4.080 2462.240 4451.280 ;
      RECT 2471.920 4.080 2473.120 4451.280 ;
      RECT 2482.800 4.080 2484.000 4451.280 ;
      RECT 2493.680 4.080 2494.880 4451.280 ;
      RECT 2504.560 4.080 2505.760 4451.280 ;
      RECT 2515.440 4.080 2516.640 4451.280 ;
      RECT 2526.320 4.080 2527.520 4451.280 ;
      RECT 2537.200 4.080 2538.400 4451.280 ;
      RECT 2548.080 4.080 2549.280 4451.280 ;
      RECT 2558.960 4.080 2560.160 4451.280 ;
      RECT 2569.840 4.080 2571.040 4451.280 ;
      RECT 2580.720 4.080 2581.920 4451.280 ;
      RECT 2591.600 4.080 2592.800 4451.280 ;
      RECT 2602.480 4.080 2603.680 4451.280 ;
      RECT 2613.360 4.080 2614.560 4451.280 ;
      RECT 2624.240 4.080 2625.440 4451.280 ;
      RECT 2635.120 4.080 2636.320 4451.280 ;
      RECT 2646.000 4.080 2647.200 4451.280 ;
      RECT 2656.880 4.080 2658.080 4451.280 ;
      RECT 2667.760 4.080 2668.960 4451.280 ;
      RECT 2678.640 4.080 2679.840 4451.280 ;
      RECT 2689.520 4.080 2690.720 4451.280 ;
      RECT 2700.400 4.080 2701.600 4451.280 ;
      RECT 2711.280 4.080 2712.480 4451.280 ;
      RECT 2722.160 4.080 2723.360 4451.280 ;
      RECT 2733.040 4.080 2734.240 4451.280 ;
    END
  END VSS
  PIN VDD
    DIRECTION INOUT ;
    USE POWER ;
    PORT
      LAYER met4 ;
      RECT 7.600 4.080 8.800 4451.280 ;
      RECT 18.480 4.080 19.680 4451.280 ;
      RECT 29.360 4.080 30.560 4451.280 ;
      RECT 40.240 4.080 41.440 4451.280 ;
      RECT 51.120 4.080 52.320 4451.280 ;
      RECT 62.000 4.080 63.200 4451.280 ;
      RECT 72.880 4.080 74.080 4451.280 ;
      RECT 83.760 4.080 84.960 4451.280 ;
      RECT 94.640 4.080 95.840 4451.280 ;
      RECT 105.520 4.080 106.720 4451.280 ;
      RECT 116.400 4.080 117.600 4451.280 ;
      RECT 127.280 4.080 128.480 4451.280 ;
      RECT 138.160 4.080 139.360 4451.280 ;
      RECT 149.040 4.080 150.240 4451.280 ;
      RECT 159.920 4.080 161.120 4451.280 ;
      RECT 170.800 4.080 172.000 4451.280 ;
      RECT 181.680 4.080 182.880 4451.280 ;
      RECT 192.560 4.080 193.760 4451.280 ;
      RECT 203.440 4.080 204.640 4451.280 ;
      RECT 214.320 4.080 215.520 4451.280 ;
      RECT 225.200 4.080 226.400 4451.280 ;
      RECT 236.080 4.080 237.280 4451.280 ;
      RECT 246.960 4.080 248.160 4451.280 ;
      RECT 257.840 4.080 259.040 4451.280 ;
      RECT 268.720 4.080 269.920 4451.280 ;
      RECT 279.600 4.080 280.800 4451.280 ;
      RECT 290.480 4.080 291.680 4451.280 ;
      RECT 301.360 4.080 302.560 4451.280 ;
      RECT 312.240 4.080 313.440 4451.280 ;
      RECT 323.120 4.080 324.320 4451.280 ;
      RECT 334.000 4.080 335.200 4451.280 ;
      RECT 344.880 4.080 346.080 4451.280 ;
      RECT 355.760 4.080 356.960 4451.280 ;
      RECT 366.640 4.080 367.840 4451.280 ;
      RECT 377.520 4.080 378.720 4451.280 ;
      RECT 388.400 4.080 389.600 4451.280 ;
      RECT 399.280 4.080 400.480 4451.280 ;
      RECT 410.160 4.080 411.360 4451.280 ;
      RECT 421.040 4.080 422.240 4451.280 ;
      RECT 431.920 4.080 433.120 4451.280 ;
      RECT 442.800 4.080 444.000 4451.280 ;
      RECT 453.680 4.080 454.880 4451.280 ;
      RECT 464.560 4.080 465.760 4451.280 ;
      RECT 475.440 4.080 476.640 4451.280 ;
      RECT 486.320 4.080 487.520 4451.280 ;
      RECT 497.200 4.080 498.400 4451.280 ;
      RECT 508.080 4.080 509.280 4451.280 ;
      RECT 518.960 4.080 520.160 4451.280 ;
      RECT 529.840 4.080 531.040 4451.280 ;
      RECT 540.720 4.080 541.920 4451.280 ;
      RECT 551.600 4.080 552.800 4451.280 ;
      RECT 562.480 4.080 563.680 4451.280 ;
      RECT 573.360 4.080 574.560 4451.280 ;
      RECT 584.240 4.080 585.440 4451.280 ;
      RECT 595.120 4.080 596.320 4451.280 ;
      RECT 606.000 4.080 607.200 4451.280 ;
      RECT 616.880 4.080 618.080 4451.280 ;
      RECT 627.760 4.080 628.960 4451.280 ;
      RECT 638.640 4.080 639.840 4451.280 ;
      RECT 649.520 4.080 650.720 4451.280 ;
      RECT 660.400 4.080 661.600 4451.280 ;
      RECT 671.280 4.080 672.480 4451.280 ;
      RECT 682.160 4.080 683.360 4451.280 ;
      RECT 693.040 4.080 694.240 4451.280 ;
      RECT 703.920 4.080 705.120 4451.280 ;
      RECT 714.800 4.080 716.000 4451.280 ;
      RECT 725.680 4.080 726.880 4451.280 ;
      RECT 736.560 4.080 737.760 4451.280 ;
      RECT 747.440 4.080 748.640 4451.280 ;
      RECT 758.320 4.080 759.520 4451.280 ;
      RECT 769.200 4.080 770.400 4451.280 ;
      RECT 780.080 4.080 781.280 4451.280 ;
      RECT 790.960 4.080 792.160 4451.280 ;
      RECT 801.840 4.080 803.040 4451.280 ;
      RECT 812.720 4.080 813.920 4451.280 ;
      RECT 823.600 4.080 824.800 4451.280 ;
      RECT 834.480 4.080 835.680 4451.280 ;
      RECT 845.360 4.080 846.560 4451.280 ;
      RECT 856.240 4.080 857.440 4451.280 ;
      RECT 867.120 4.080 868.320 4451.280 ;
      RECT 878.000 4.080 879.200 4451.280 ;
      RECT 888.880 4.080 890.080 4451.280 ;
      RECT 899.760 4.080 900.960 4451.280 ;
      RECT 910.640 4.080 911.840 4451.280 ;
      RECT 921.520 4.080 922.720 4451.280 ;
      RECT 932.400 4.080 933.600 4451.280 ;
      RECT 943.280 4.080 944.480 4451.280 ;
      RECT 954.160 4.080 955.360 4451.280 ;
      RECT 965.040 4.080 966.240 4451.280 ;
      RECT 975.920 4.080 977.120 4451.280 ;
      RECT 986.800 4.080 988.000 4451.280 ;
      RECT 997.680 4.080 998.880 4451.280 ;
      RECT 1008.560 4.080 1009.760 4451.280 ;
      RECT 1019.440 4.080 1020.640 4451.280 ;
      RECT 1030.320 4.080 1031.520 4451.280 ;
      RECT 1041.200 4.080 1042.400 4451.280 ;
      RECT 1052.080 4.080 1053.280 4451.280 ;
      RECT 1062.960 4.080 1064.160 4451.280 ;
      RECT 1073.840 4.080 1075.040 4451.280 ;
      RECT 1084.720 4.080 1085.920 4451.280 ;
      RECT 1095.600 4.080 1096.800 4451.280 ;
      RECT 1106.480 4.080 1107.680 4451.280 ;
      RECT 1117.360 4.080 1118.560 4451.280 ;
      RECT 1128.240 4.080 1129.440 4451.280 ;
      RECT 1139.120 4.080 1140.320 4451.280 ;
      RECT 1150.000 4.080 1151.200 4451.280 ;
      RECT 1160.880 4.080 1162.080 4451.280 ;
      RECT 1171.760 4.080 1172.960 4451.280 ;
      RECT 1182.640 4.080 1183.840 4451.280 ;
      RECT 1193.520 4.080 1194.720 4451.280 ;
      RECT 1204.400 4.080 1205.600 4451.280 ;
      RECT 1215.280 4.080 1216.480 4451.280 ;
      RECT 1226.160 4.080 1227.360 4451.280 ;
      RECT 1237.040 4.080 1238.240 4451.280 ;
      RECT 1247.920 4.080 1249.120 4451.280 ;
      RECT 1258.800 4.080 1260.000 4451.280 ;
      RECT 1269.680 4.080 1270.880 4451.280 ;
      RECT 1280.560 4.080 1281.760 4451.280 ;
      RECT 1291.440 4.080 1292.640 4451.280 ;
      RECT 1302.320 4.080 1303.520 4451.280 ;
      RECT 1313.200 4.080 1314.400 4451.280 ;
      RECT 1324.080 4.080 1325.280 4451.280 ;
      RECT 1334.960 4.080 1336.160 4451.280 ;
      RECT 1345.840 4.080 1347.040 4451.280 ;
      RECT 1356.720 4.080 1357.920 4451.280 ;
      RECT 1367.600 4.080 1368.800 4451.280 ;
      RECT 1378.480 4.080 1379.680 4451.280 ;
      RECT 1389.360 4.080 1390.560 4451.280 ;
      RECT 1400.240 4.080 1401.440 4451.280 ;
      RECT 1411.120 4.080 1412.320 4451.280 ;
      RECT 1422.000 4.080 1423.200 4451.280 ;
      RECT 1432.880 4.080 1434.080 4451.280 ;
      RECT 1443.760 4.080 1444.960 4451.280 ;
      RECT 1454.640 4.080 1455.840 4451.280 ;
      RECT 1465.520 4.080 1466.720 4451.280 ;
      RECT 1476.400 4.080 1477.600 4451.280 ;
      RECT 1487.280 4.080 1488.480 4451.280 ;
      RECT 1498.160 4.080 1499.360 4451.280 ;
      RECT 1509.040 4.080 1510.240 4451.280 ;
      RECT 1519.920 4.080 1521.120 4451.280 ;
      RECT 1530.800 4.080 1532.000 4451.280 ;
      RECT 1541.680 4.080 1542.880 4451.280 ;
      RECT 1552.560 4.080 1553.760 4451.280 ;
      RECT 1563.440 4.080 1564.640 4451.280 ;
      RECT 1574.320 4.080 1575.520 4451.280 ;
      RECT 1585.200 4.080 1586.400 4451.280 ;
      RECT 1596.080 4.080 1597.280 4451.280 ;
      RECT 1606.960 4.080 1608.160 4451.280 ;
      RECT 1617.840 4.080 1619.040 4451.280 ;
      RECT 1628.720 4.080 1629.920 4451.280 ;
      RECT 1639.600 4.080 1640.800 4451.280 ;
      RECT 1650.480 4.080 1651.680 4451.280 ;
      RECT 1661.360 4.080 1662.560 4451.280 ;
      RECT 1672.240 4.080 1673.440 4451.280 ;
      RECT 1683.120 4.080 1684.320 4451.280 ;
      RECT 1694.000 4.080 1695.200 4451.280 ;
      RECT 1704.880 4.080 1706.080 4451.280 ;
      RECT 1715.760 4.080 1716.960 4451.280 ;
      RECT 1726.640 4.080 1727.840 4451.280 ;
      RECT 1737.520 4.080 1738.720 4451.280 ;
      RECT 1748.400 4.080 1749.600 4451.280 ;
      RECT 1759.280 4.080 1760.480 4451.280 ;
      RECT 1770.160 4.080 1771.360 4451.280 ;
      RECT 1781.040 4.080 1782.240 4451.280 ;
      RECT 1791.920 4.080 1793.120 4451.280 ;
      RECT 1802.800 4.080 1804.000 4451.280 ;
      RECT 1813.680 4.080 1814.880 4451.280 ;
      RECT 1824.560 4.080 1825.760 4451.280 ;
      RECT 1835.440 4.080 1836.640 4451.280 ;
      RECT 1846.320 4.080 1847.520 4451.280 ;
      RECT 1857.200 4.080 1858.400 4451.280 ;
      RECT 1868.080 4.080 1869.280 4451.280 ;
      RECT 1878.960 4.080 1880.160 4451.280 ;
      RECT 1889.840 4.080 1891.040 4451.280 ;
      RECT 1900.720 4.080 1901.920 4451.280 ;
      RECT 1911.600 4.080 1912.800 4451.280 ;
      RECT 1922.480 4.080 1923.680 4451.280 ;
      RECT 1933.360 4.080 1934.560 4451.280 ;
      RECT 1944.240 4.080 1945.440 4451.280 ;
      RECT 1955.120 4.080 1956.320 4451.280 ;
      RECT 1966.000 4.080 1967.200 4451.280 ;
      RECT 1976.880 4.080 1978.080 4451.280 ;
      RECT 1987.760 4.080 1988.960 4451.280 ;
      RECT 1998.640 4.080 1999.840 4451.280 ;
      RECT 2009.520 4.080 2010.720 4451.280 ;
      RECT 2020.400 4.080 2021.600 4451.280 ;
      RECT 2031.280 4.080 2032.480 4451.280 ;
      RECT 2042.160 4.080 2043.360 4451.280 ;
      RECT 2053.040 4.080 2054.240 4451.280 ;
      RECT 2063.920 4.080 2065.120 4451.280 ;
      RECT 2074.800 4.080 2076.000 4451.280 ;
      RECT 2085.680 4.080 2086.880 4451.280 ;
      RECT 2096.560 4.080 2097.760 4451.280 ;
      RECT 2107.440 4.080 2108.640 4451.280 ;
      RECT 2118.320 4.080 2119.520 4451.280 ;
      RECT 2129.200 4.080 2130.400 4451.280 ;
      RECT 2140.080 4.080 2141.280 4451.280 ;
      RECT 2150.960 4.080 2152.160 4451.280 ;
      RECT 2161.840 4.080 2163.040 4451.280 ;
      RECT 2172.720 4.080 2173.920 4451.280 ;
      RECT 2183.600 4.080 2184.800 4451.280 ;
      RECT 2194.480 4.080 2195.680 4451.280 ;
      RECT 2205.360 4.080 2206.560 4451.280 ;
      RECT 2216.240 4.080 2217.440 4451.280 ;
      RECT 2227.120 4.080 2228.320 4451.280 ;
      RECT 2238.000 4.080 2239.200 4451.280 ;
      RECT 2248.880 4.080 2250.080 4451.280 ;
      RECT 2259.760 4.080 2260.960 4451.280 ;
      RECT 2270.640 4.080 2271.840 4451.280 ;
      RECT 2281.520 4.080 2282.720 4451.280 ;
      RECT 2292.400 4.080 2293.600 4451.280 ;
      RECT 2303.280 4.080 2304.480 4451.280 ;
      RECT 2314.160 4.080 2315.360 4451.280 ;
      RECT 2325.040 4.080 2326.240 4451.280 ;
      RECT 2335.920 4.080 2337.120 4451.280 ;
      RECT 2346.800 4.080 2348.000 4451.280 ;
      RECT 2357.680 4.080 2358.880 4451.280 ;
      RECT 2368.560 4.080 2369.760 4451.280 ;
      RECT 2379.440 4.080 2380.640 4451.280 ;
      RECT 2390.320 4.080 2391.520 4451.280 ;
      RECT 2401.200 4.080 2402.400 4451.280 ;
      RECT 2412.080 4.080 2413.280 4451.280 ;
      RECT 2422.960 4.080 2424.160 4451.280 ;
      RECT 2433.840 4.080 2435.040 4451.280 ;
      RECT 2444.720 4.080 2445.920 4451.280 ;
      RECT 2455.600 4.080 2456.800 4451.280 ;
      RECT 2466.480 4.080 2467.680 4451.280 ;
      RECT 2477.360 4.080 2478.560 4451.280 ;
      RECT 2488.240 4.080 2489.440 4451.280 ;
      RECT 2499.120 4.080 2500.320 4451.280 ;
      RECT 2510.000 4.080 2511.200 4451.280 ;
      RECT 2520.880 4.080 2522.080 4451.280 ;
      RECT 2531.760 4.080 2532.960 4451.280 ;
      RECT 2542.640 4.080 2543.840 4451.280 ;
      RECT 2553.520 4.080 2554.720 4451.280 ;
      RECT 2564.400 4.080 2565.600 4451.280 ;
      RECT 2575.280 4.080 2576.480 4451.280 ;
      RECT 2586.160 4.080 2587.360 4451.280 ;
      RECT 2597.040 4.080 2598.240 4451.280 ;
      RECT 2607.920 4.080 2609.120 4451.280 ;
      RECT 2618.800 4.080 2620.000 4451.280 ;
      RECT 2629.680 4.080 2630.880 4451.280 ;
      RECT 2640.560 4.080 2641.760 4451.280 ;
      RECT 2651.440 4.080 2652.640 4451.280 ;
      RECT 2662.320 4.080 2663.520 4451.280 ;
      RECT 2673.200 4.080 2674.400 4451.280 ;
      RECT 2684.080 4.080 2685.280 4451.280 ;
      RECT 2694.960 4.080 2696.160 4451.280 ;
      RECT 2705.840 4.080 2707.040 4451.280 ;
      RECT 2716.720 4.080 2717.920 4451.280 ;
      RECT 2727.600 4.080 2728.800 4451.280 ;
    END
  END VDD
  OBS
    LAYER met1 ;
    RECT 0 0 2739.300 4455.360 ;
    LAYER met2 ;
    RECT 0 0 2739.300 4455.360 ;
    LAYER met3 ;
    RECT 0 0 2739.300 4455.360 ;
    LAYER met4 ;
    RECT 0 0 2739.300 4455.360 ;
  END
END fakeram_w64_l16384

END LIBRARY
